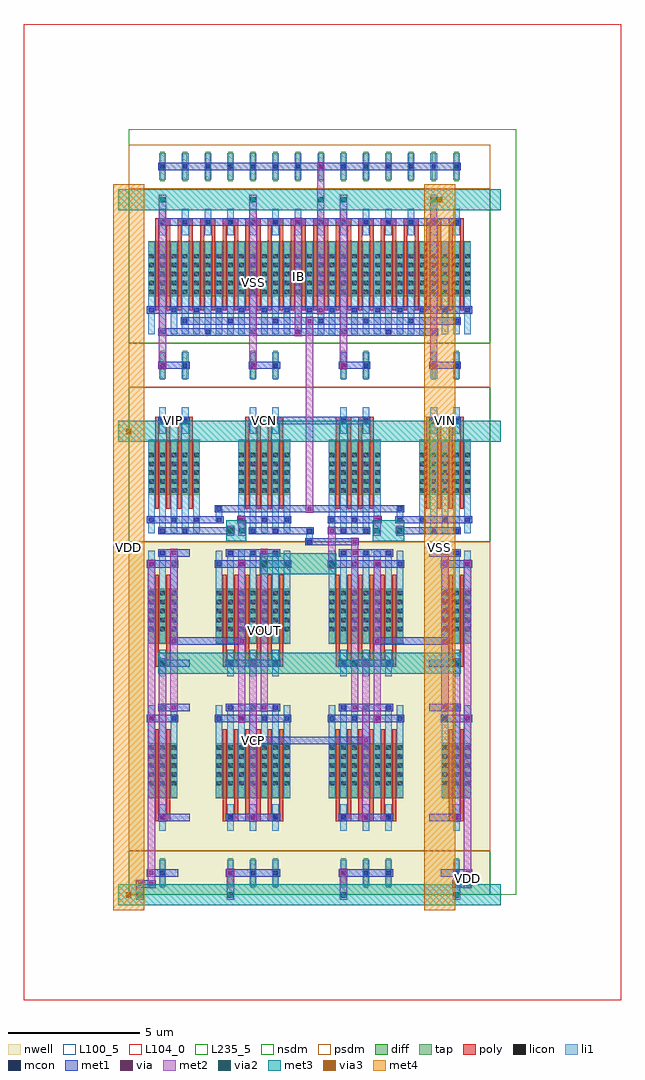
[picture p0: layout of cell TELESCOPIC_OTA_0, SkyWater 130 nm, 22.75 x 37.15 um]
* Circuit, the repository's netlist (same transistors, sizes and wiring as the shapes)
* NGSPICE file created from TELESCOPIC_OTA_0.ext - technology: sky130A

.subckt NMOS_4T_28886488_X2_Y1_1774869527 a_230_357# a_200_252# a_147_357# a_241_1232#
X0 a_230_357# a_200_252# a_147_357# a_241_1232# sky130_fd_pr__nfet_01v8 ad=0.294 pd=2.38 as=0.5565 ps=4.73 w=2.1 l=0.15 M=4
.ends

.subckt PMOS_S_89697479_X1_Y2_1774869529 a_230_357# a_200_252# w_0_0#
X0 a_230_357# a_200_252# w_0_0# w_0_0# sky130_fd_pr__pfet_01v8 ad=0.294 pd=2.38 as=0.5565 ps=4.73 w=2.1 l=0.15 M=4
.ends

.subckt PMOS_4T_8744924_X3_Y2_1774869528 a_230_357# a_200_252# a_147_357# w_0_0#
X0 a_230_357# a_200_252# a_147_357# w_0_0# sky130_fd_pr__pfet_01v8 ad=0.294 pd=2.38 as=0.5565 ps=4.73 w=2.1 l=0.15 M=12
.ends

.subckt SCM_NMOS_72619132_X7_Y1_1774869530 a_200_252# a_402_357# a_147_357#
X0 a_200_252# a_200_252# a_147_357# a_147_357# sky130_fd_pr__nfet_01v8 ad=0.294 pd=2.38 as=0.294 ps=2.38 w=2.1 l=0.15 M=14
X1 a_147_357# a_200_252# a_402_357# a_147_357# sky130_fd_pr__nfet_01v8 ad=0.294 pd=2.38 as=0.294 ps=2.38 w=2.1 l=0.15 M=14
.ends

.subckt TELESCOPIC_OTA_0 IB VCN VOUT VIP VIN VCP VSS VDD
XNMOS_4T_28886488_X2_Y1_1774869527_2 VOUT VCN m1_1860_2828# VSS NMOS_4T_28886488_X2_Y1_1774869527
XNMOS_4T_28886488_X2_Y1_1774869527_3 m2_230_1727# VCN m1_430_2744# VSS NMOS_4T_28886488_X2_Y1_1774869527
XPMOS_S_89697479_X1_Y2_1774869529_0 m1_312_1904# m2_230_1727# VDD PMOS_S_89697479_X1_Y2_1774869529
XPMOS_S_89697479_X1_Y2_1774869529_1 m1_1860_1904# m2_230_1727# VDD PMOS_S_89697479_X1_Y2_1774869529
XPMOS_4T_8744924_X3_Y2_1774869528_1 m2_230_1727# VCP m1_1860_1904# VDD PMOS_4T_8744924_X3_Y2_1774869528
XPMOS_4T_8744924_X3_Y2_1774869528_0 VOUT VCP m1_312_1904# VDD PMOS_4T_8744924_X3_Y2_1774869528
XSCM_NMOS_72619132_X7_Y1_1774869530_0 IB li_663_2839# VSS SCM_NMOS_72619132_X7_Y1_1774869530
XNMOS_4T_28886488_X2_Y1_1774869527_0 m1_1860_2828# VIN li_663_2839# VSS NMOS_4T_28886488_X2_Y1_1774869527
XNMOS_4T_28886488_X2_Y1_1774869527_1 m1_430_2744# VIP li_663_2839# VSS NMOS_4T_28886488_X2_Y1_1774869527
.ends

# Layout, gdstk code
from math import pi, radians
import gdstk
lib = gdstk.Library(unit=1e-6, precision=1e-09)
def R(c, l, rs):  # rectangles x0, y0, x1, y1
    for r in rs: c.add(gdstk.rectangle(r[:2], r[2:], *l))
def A(c, l, x, y, w, h, nx, ny, dx, dy):  # array of equal rectangles
    R(c, l, [(x+i*dx, y+j*dy, x+i*dx+w, y+j*dy+h) for i in range(nx) for j in range(ny)])
def P(c, l, *ps):  # polygons
    for p in ps: c.add(gdstk.Polygon(p, *l))
nwell = (64, 20)
diff = (65, 20)
tap = (65, 44)
poly = (66, 20)
licon = (66, 44)
li1 = (67, 20)
mcon = (67, 44)
met1 = (68, 20)
via = (68, 44)
met2 = (69, 20)
via2 = (69, 44)
met3 = (70, 20)
via3 = (70, 44)
met4 = (71, 20)
nsdm = (93, 44)
psdm = (94, 20)
L100_5 = (100, 5)
L104_0 = (104, 0)
L235_5 = (235, 5)

scm_nmos_72619132_x7_y1_ = lib.new_cell('SCM_NMOS_72619132_X7_Y1_1774869530')
R(scm_nmos_72619132_x7_y1_, diff, [(0.735,1.785,13.025,3.885)])
A(scm_nmos_72619132_x7_y1_, tap, 1.205, 6.16, 0.17, 1.12, 14, 1, 0.86, 0)
A(scm_nmos_72619132_x7_y1_, poly, 1, 1.26, 0.15, 3.36, 28, 1, 0.43, 0)
A(scm_nmos_72619132_x7_y1_, poly, 1, 4.485, 0.58, 0.27, 14, 1, 0.86, 0)
A(scm_nmos_72619132_x7_y1_, licon, 0.775, 1.865, 0.17, 0.17, 3, 5, 0.43, 0.34)
A(scm_nmos_72619132_x7_y1_, licon, 1.635, 1.865, 0.17, 0.17, 3, 5, 0.43, 0.34)
A(scm_nmos_72619132_x7_y1_, licon, 2.495, 1.865, 0.17, 0.17, 3, 5, 0.43, 0.34)
A(scm_nmos_72619132_x7_y1_, licon, 3.355, 1.865, 0.17, 0.17, 3, 5, 0.43, 0.34)
A(scm_nmos_72619132_x7_y1_, licon, 4.215, 1.865, 0.17, 0.17, 3, 5, 0.43, 0.34)
A(scm_nmos_72619132_x7_y1_, licon, 5.075, 1.865, 0.17, 0.17, 3, 5, 0.43, 0.34)
A(scm_nmos_72619132_x7_y1_, licon, 5.935, 1.865, 0.17, 0.17, 3, 5, 0.43, 0.34)
A(scm_nmos_72619132_x7_y1_, licon, 6.795, 1.865, 0.17, 0.17, 3, 5, 0.43, 0.34)
A(scm_nmos_72619132_x7_y1_, licon, 7.655, 1.865, 0.17, 0.17, 3, 5, 0.43, 0.34)
A(scm_nmos_72619132_x7_y1_, licon, 8.515, 1.865, 0.17, 0.17, 3, 5, 0.43, 0.34)
A(scm_nmos_72619132_x7_y1_, licon, 9.375, 1.865, 0.17, 0.17, 3, 5, 0.43, 0.34)
A(scm_nmos_72619132_x7_y1_, licon, 10.235, 1.865, 0.17, 0.17, 3, 5, 0.43, 0.34)
A(scm_nmos_72619132_x7_y1_, licon, 11.095, 1.865, 0.17, 0.17, 3, 5, 0.43, 0.34)
A(scm_nmos_72619132_x7_y1_, licon, 11.955, 1.865, 0.17, 0.17, 3, 5, 0.43, 0.34)
A(scm_nmos_72619132_x7_y1_, licon, 1.205, 4.535, 0.17, 0.17, 14, 2, 0.86, 2.1)
A(scm_nmos_72619132_x7_y1_, li1, 0.735, 0.335, 0.25, 3.53, 29, 1, 0.43, 0)
A(scm_nmos_72619132_x7_y1_, li1, 1.165, 4.115, 0.25, 1.01, 14, 2, 0.86, 2.1)
A(scm_nmos_72619132_x7_y1_, mcon, 1.205, 0.335, 0.17, 0.17, 7, 1, 1.72, 0)
A(scm_nmos_72619132_x7_y1_, mcon, 2.065, 0.755, 0.17, 0.17, 7, 1, 1.72, 0)
A(scm_nmos_72619132_x7_y1_, mcon, 0.775, 1.175, 0.17, 0.17, 15, 1, 0.86, 0)
A(scm_nmos_72619132_x7_y1_, mcon, 1.205, 4.535, 0.17, 0.17, 14, 2, 0.86, 2.1)
R(scm_nmos_72619132_x7_y1_, met1, [(1.12,0.28,11.78,0.56), (1.98,0.7,12.64,0.98), (0.69,1.12,13.07,1.4), (1.12,4.48,12.64,4.76), (1.12,6.58,12.64,6.86)])
R(scm_nmos_72619132_x7_y1_, via, [(6.375,0.345,6.525,0.495), (7.235,1.185,7.385,1.335), (6.375,4.545,6.525,4.695), (7.235,6.645,7.385,6.795)])
R(scm_nmos_72619132_x7_y1_, met2, [(6.31,0.26,6.59,4.78), (7.17,1.1,7.45,6.88)])
R(scm_nmos_72619132_x7_y1_, nsdm, [(0,0,13.76,5.88)])
R(scm_nmos_72619132_x7_y1_, psdm, [(0,5.88,13.76,7.56)])
R(scm_nmos_72619132_x7_y1_, L100_5, [(0,0,13.76,7.56)])

pmos_s_89697479_x1_y2_17 = lib.new_cell('PMOS_S_89697479_X1_Y2_1774869529')
R(pmos_s_89697479_x1_y2_17, nwell, [(0,0,2.58,13.44)])
R(pmos_s_89697479_x1_y2_17, diff, [(0.735,1.785,1.845,3.885), (0.735,7.665,1.845,9.765)])
R(pmos_s_89697479_x1_y2_17, tap, [(1.205,12.04,1.375,13.16)])
R(pmos_s_89697479_x1_y2_17, poly, [(1,1.26,1.15,4.62), (1.43,1.26,1.58,4.62), (1,4.485,1.58,4.755), (1,7.14,1.15,10.5), (1.43,7.14,1.58,10.5), (1,10.365,1.58,10.635)])
A(pmos_s_89697479_x1_y2_17, licon, 0.775, 1.865, 0.17, 0.17, 3, 5, 0.43, 0.34)
A(pmos_s_89697479_x1_y2_17, licon, 0.775, 7.745, 0.17, 0.17, 3, 5, 0.43, 0.34)
R(pmos_s_89697479_x1_y2_17, licon, [(1.205,4.535,1.375,4.705), (1.205,10.415,1.375,10.585), (1.205,12.515,1.375,12.685), (1.205,12.515,1.375,12.685)])
A(pmos_s_89697479_x1_y2_17, li1, 0.735, 0.335, 0.25, 3.53, 3, 2, 0.43, 5.88)
R(pmos_s_89697479_x1_y2_17, li1, [(1.165,4.115,1.415,5.125), (1.165,9.995,1.415,11.005), (1.165,12.095,1.415,13.105)])
R(pmos_s_89697479_x1_y2_17, mcon, [(1.205,0.335,1.375,0.505), (0.775,0.755,0.945,0.925), (1.635,0.755,1.805,0.925), (1.205,4.535,1.375,4.705), (1.205,6.215,1.375,6.385), (0.775,6.635,0.945,6.805), (1.635,6.635,1.805,6.805), (1.205,10.415,1.375,10.585), (1.205,12.515,1.375,12.685)])
A(pmos_s_89697479_x1_y2_17, met1, 0.69, 0.7, 1.2, 0.28, 1, 3, 0, 5.88)
R(pmos_s_89697479_x1_y2_17, met1, [(0.26,0.28,1.46,0.56), (0.26,4.48,1.46,4.76), (0.26,6.16,1.46,6.44), (0.26,10.36,1.46,10.64)])
A(pmos_s_89697479_x1_y2_17, via, 1.645, 0.765, 0.15, 0.15, 1, 3, 0, 5.88)
R(pmos_s_89697479_x1_y2_17, via, [(0.785,0.345,0.935,0.495), (1.215,4.545,1.365,4.695), (0.785,6.225,0.935,6.375), (1.215,10.425,1.365,10.575)])
R(pmos_s_89697479_x1_y2_17, met2, [(0.72,0.26,1,6.46), (1.58,0.68,1.86,12.76), (1.15,4.46,1.43,10.66)])
R(pmos_s_89697479_x1_y2_17, nsdm, [(0,11.76,2.58,13.44)])
R(pmos_s_89697479_x1_y2_17, psdm, [(0,0,2.58,11.76)])
R(pmos_s_89697479_x1_y2_17, L100_5, [(0,0,2.58,13.44)])

nmos_4t_28886488_x2_y1_1 = lib.new_cell('NMOS_4T_28886488_X2_Y1_1774869527')
R(nmos_4t_28886488_x2_y1_1, diff, [(0.735,1.785,2.705,3.885)])
R(nmos_4t_28886488_x2_y1_1, tap, [(1.205,6.16,1.375,7.28), (2.065,6.16,2.235,7.28)])
A(nmos_4t_28886488_x2_y1_1, poly, 1, 1.26, 0.15, 3.36, 4, 1, 0.43, 0)
R(nmos_4t_28886488_x2_y1_1, poly, [(1,4.485,1.58,4.755), (1.86,4.485,2.44,4.755)])
A(nmos_4t_28886488_x2_y1_1, licon, 0.775, 1.865, 0.17, 0.17, 3, 5, 0.43, 0.34)
A(nmos_4t_28886488_x2_y1_1, licon, 1.635, 1.865, 0.17, 0.17, 3, 5, 0.43, 0.34)
R(nmos_4t_28886488_x2_y1_1, licon, [(1.205,4.535,1.375,4.705), (2.065,4.535,2.235,4.705), (1.205,6.635,1.375,6.805), (2.065,6.635,2.235,6.805)])
A(nmos_4t_28886488_x2_y1_1, li1, 0.735, 0.335, 0.25, 3.53, 5, 1, 0.43, 0)
R(nmos_4t_28886488_x2_y1_1, li1, [(1.165,4.115,1.415,5.125), (2.025,4.115,2.275,5.125), (1.165,6.215,1.415,7.225), (2.025,6.215,2.275,7.225)])
A(nmos_4t_28886488_x2_y1_1, mcon, 0.775, 0.755, 0.17, 0.17, 3, 1, 0.86, 0)
R(nmos_4t_28886488_x2_y1_1, mcon, [(1.205,0.335,1.375,0.505), (2.065,0.335,2.235,0.505), (1.205,4.535,1.375,4.705), (2.065,4.535,2.235,4.705), (1.205,6.635,1.375,6.805), (2.065,6.635,2.235,6.805)])
R(nmos_4t_28886488_x2_y1_1, met1, [(1.12,0.28,2.32,0.56), (0.69,0.7,2.75,0.98), (1.12,4.48,2.32,4.76), (1.12,6.58,2.32,6.86)])
R(nmos_4t_28886488_x2_y1_1, nsdm, [(0,0,3.44,5.88)])
R(nmos_4t_28886488_x2_y1_1, psdm, [(0,5.88,3.44,7.56)])
R(nmos_4t_28886488_x2_y1_1, L100_5, [(0,0,3.44,7.56)])

pmos_4t_8744924_x3_y2_17 = lib.new_cell('PMOS_4T_8744924_X3_Y2_1774869528')
R(pmos_4t_8744924_x3_y2_17, nwell, [(0,0,4.3,13.44)])
R(pmos_4t_8744924_x3_y2_17, diff, [(0.735,1.785,3.565,3.885), (0.735,7.665,3.565,9.765)])
A(pmos_4t_8744924_x3_y2_17, tap, 1.205, 12.04, 0.17, 1.12, 3, 1, 0.86, 0)
A(pmos_4t_8744924_x3_y2_17, poly, 1, 1.26, 0.15, 3.36, 6, 2, 0.43, 5.88)
A(pmos_4t_8744924_x3_y2_17, poly, 1, 4.485, 0.58, 0.27, 3, 2, 0.86, 5.88)
A(pmos_4t_8744924_x3_y2_17, licon, 0.775, 1.865, 0.17, 0.17, 3, 5, 0.43, 0.34)
A(pmos_4t_8744924_x3_y2_17, licon, 1.635, 1.865, 0.17, 0.17, 3, 5, 0.43, 0.34)
A(pmos_4t_8744924_x3_y2_17, licon, 2.495, 1.865, 0.17, 0.17, 3, 5, 0.43, 0.34)
A(pmos_4t_8744924_x3_y2_17, licon, 1.205, 4.535, 0.17, 0.17, 3, 2, 0.86, 5.88)
A(pmos_4t_8744924_x3_y2_17, licon, 0.775, 7.745, 0.17, 0.17, 3, 5, 0.43, 0.34)
A(pmos_4t_8744924_x3_y2_17, licon, 1.635, 7.745, 0.17, 0.17, 3, 5, 0.43, 0.34)
A(pmos_4t_8744924_x3_y2_17, licon, 2.495, 7.745, 0.17, 0.17, 3, 5, 0.43, 0.34)
R(pmos_4t_8744924_x3_y2_17, licon, [(1.205,12.515,1.375,12.685), (1.205,12.515,1.375,12.685), (2.065,12.515,2.235,12.685), (2.065,12.515,2.235,12.685), (2.925,12.515,3.095,12.685), (2.925,12.515,3.095,12.685)])
A(pmos_4t_8744924_x3_y2_17, li1, 0.735, 0.335, 0.25, 3.53, 7, 2, 0.43, 5.88)
A(pmos_4t_8744924_x3_y2_17, li1, 1.165, 4.115, 0.25, 1.01, 3, 2, 0.86, 5.88)
A(pmos_4t_8744924_x3_y2_17, li1, 1.165, 12.095, 0.25, 1.01, 3, 1, 0.86, 0)
A(pmos_4t_8744924_x3_y2_17, mcon, 1.205, 0.335, 0.17, 0.17, 3, 2, 0.86, 4.2)
A(pmos_4t_8744924_x3_y2_17, mcon, 0.775, 0.755, 0.17, 0.17, 4, 2, 0.86, 5.88)
A(pmos_4t_8744924_x3_y2_17, mcon, 1.205, 6.215, 0.17, 0.17, 3, 2, 0.86, 4.2)
A(pmos_4t_8744924_x3_y2_17, mcon, 1.205, 12.515, 0.17, 0.17, 3, 1, 0.86, 0)
R(pmos_4t_8744924_x3_y2_17, met1, [(1.12,0.28,3.18,0.56), (0.69,0.7,3.61,0.98), (1.12,4.48,3.18,4.76), (1.12,6.16,3.18,6.44), (0.69,6.58,3.61,6.86), (1.12,10.36,3.18,10.64), (1.12,12.46,3.18,12.74)])
R(pmos_4t_8744924_x3_y2_17, via, [(1.645,0.345,1.795,0.495), (2.505,0.765,2.655,0.915), (2.075,4.545,2.225,4.695), (1.645,6.225,1.795,6.375), (2.505,6.645,2.655,6.795), (2.075,10.425,2.225,10.575)])
R(pmos_4t_8744924_x3_y2_17, met2, [(1.58,0.26,1.86,6.46), (2.44,0.68,2.72,6.88), (2.01,4.46,2.29,10.66)])
R(pmos_4t_8744924_x3_y2_17, nsdm, [(0,11.76,4.3,13.44)])
R(pmos_4t_8744924_x3_y2_17, psdm, [(0,0,4.3,11.76)])
R(pmos_4t_8744924_x3_y2_17, L100_5, [(0,0,4.3,13.44)])

telescopic_ota_0 = lib.new_cell('TELESCOPIC_OTA_0')
R(telescopic_ota_0, li1, [(6.755,13.355,7.005,13.525), (6.755,13.355,7.005,13.525), (6.755,13.44,7.005,13.86), (6.755,13.775,7.005,13.945), (6.755,13.775,7.005,13.945), (3.315,14.195,3.565,14.365), (3.315,14.195,3.565,14.365), (3.315,14.195,3.565,14.365), (3.315,14.195,3.565,14.365), (10.195,14.195,10.445,14.365), (10.195,14.195,10.445,14.365), (10.195,14.195,10.445,14.365), (10.195,14.195,10.445,14.365), (3.315,14.28,3.565,14.7), (10.195,14.28,10.445,14.7), (3.315,14.615,3.565,14.785), (3.315,14.615,3.565,14.785), (3.315,14.615,3.565,14.785), (3.315,14.615,3.565,14.785), (10.195,14.615,10.445,14.785), (10.195,14.615,10.445,14.785), (10.195,14.615,10.445,14.785), (10.195,14.615,10.445,14.785)])
R(telescopic_ota_0, mcon, [(6.795,13.355,6.965,13.525), (6.795,13.355,6.965,13.525), (6.795,13.775,6.965,13.945), (6.795,13.775,6.965,13.945), (3.355,14.195,3.525,14.365), (3.355,14.195,3.525,14.365), (3.355,14.195,3.525,14.365), (3.355,14.195,3.525,14.365), (10.235,14.195,10.405,14.365), (10.235,14.195,10.405,14.365), (10.235,14.195,10.405,14.365), (10.235,14.195,10.405,14.365), (3.355,14.615,3.525,14.785), (3.355,14.615,3.525,14.785), (3.355,14.615,3.525,14.785), (3.355,14.615,3.525,14.785), (10.235,14.615,10.405,14.785), (10.235,14.615,10.405,14.785), (10.235,14.615,10.405,14.785), (10.235,14.615,10.405,14.785)])
R(telescopic_ota_0, met1, [(0.27,0.28,0.59,0.56), (0.27,0.28,0.59,0.56), (0.27,0.28,0.59,0.56), (0.27,0.28,0.59,0.56), (0.43,0.28,0.86,0.56), (0.7,0.28,1.02,0.56), (0.7,0.28,1.02,0.56), (0.7,0.28,1.02,0.56), (0.7,0.28,1.02,0.56), (12.31,0.28,12.63,0.56), (12.31,0.28,12.63,0.56), (12.31,0.28,12.63,0.56), (12.31,0.28,12.63,0.56), (12.31,0.28,12.63,0.56), (12.47,0.28,12.9,0.56), (12.74,0.28,13.06,0.56), (12.74,0.28,13.06,0.56), (12.74,0.28,13.06,0.56), (12.74,0.28,13.06,0.56), (12.74,0.28,13.06,0.56), (3.71,0.7,4.03,0.98), (3.71,0.7,4.03,0.98), (8.01,0.7,8.33,0.98), (8.01,0.7,8.33,0.98), (8.01,0.7,8.33,0.98), (4.57,5.74,4.89,6.02), (4.57,5.74,4.89,6.02), (4.73,5.74,9.03,6.02), (8.87,5.74,9.19,6.02), (8.87,5.74,9.19,6.02), (1.56,9.52,1.88,9.8), (1.56,9.52,1.88,9.8), (1.72,9.52,4.3,9.8), (4.14,9.52,4.46,9.8), (4.14,9.52,4.46,9.8), (9.3,9.52,9.62,9.8), (9.3,9.52,9.62,9.8), (9.46,9.52,12.04,9.8), (11.88,9.52,12.2,9.8), (11.88,9.52,12.2,9.8), (6.71,13.3,7.05,13.58), (6.71,13.3,7.05,13.58), (6.88,13.3,8.6,13.58), (8.44,13.3,8.76,13.58), (8.44,13.3,8.76,13.58), (2.15,13.72,3.87,14), (3.71,13.72,4.03,14), (5.59,13.72,6.88,14), (6.71,13.72,7.05,14), (6.71,13.72,7.05,14), (7.58,13.72,7.9,14), (7.58,13.72,7.9,14), (7.74,13.72,8.17,14), (10.16,13.72,10.48,14), (10.32,13.72,11.61,14), (2.58,14.14,3.44,14.42), (3.27,14.14,3.61,14.42), (3.27,14.14,3.61,14.42), (3.27,14.14,3.61,14.42), (3.27,14.14,3.61,14.42), (4.14,14.14,4.46,14.42), (4.14,14.14,4.46,14.42), (9.3,14.14,9.62,14.42), (9.3,14.14,9.62,14.42), (10.15,14.14,10.49,14.42), (10.15,14.14,10.49,14.42), (10.15,14.14,10.49,14.42), (10.15,14.14,10.49,14.42), (10.32,14.14,11.18,14.42), (3.27,14.56,3.61,14.84), (3.27,14.56,3.61,14.84), (3.27,14.56,3.61,14.84), (3.27,14.56,3.61,14.84), (3.44,14.56,10.32,14.84), (6.72,14.56,7.04,14.84), (6.72,14.56,7.04,14.84), (10.15,14.56,10.49,14.84), (10.15,14.56,10.49,14.84), (10.15,14.56,10.49,14.84), (10.15,14.56,10.49,14.84), (5.59,17.92,8.17,18.2), (1.13,20.02,1.45,20.3), (1.13,20.02,1.45,20.3), (1.13,20.02,1.45,20.3), (4.57,20.02,4.89,20.3), (4.57,20.02,4.89,20.3), (4.57,20.02,4.89,20.3), (4.57,20.02,4.89,20.3), (4.57,20.02,4.89,20.3), (8.01,20.02,8.33,20.3), (8.01,20.02,8.33,20.3), (8.01,20.02,8.33,20.3), (8.01,20.02,8.33,20.3), (11.45,20.02,11.77,20.3), (11.45,20.02,11.77,20.3), (6.72,21.7,7.04,21.98), (6.72,21.7,7.04,21.98)])
P(telescopic_ota_0, met1, [(0,0),(0,0),(0,0),(0,0)],
  [(0,0),(0,0),(0,0),(0,0)],
  [(0,0),(0,0),(0,0),(0,0)],
  [(0,0),(0,0),(0,0),(0,0)],
  [(0,0),(0,0),(0,0),(0,0)],
  [(0,0),(0,0),(0,0),(0,0)],
  [(0,0),(0,0),(0,0),(0,0)],
  [(0,0),(0,0),(0,0),(0,0)],
  [(0,0),(0,0),(0,0),(0,0)],
  [(0,0),(0,0),(0,0),(0,0)],
  [(0,0),(0,0),(0,0),(0,0)],
  [(0,0),(0,0),(0,0),(0,0)],
  [(0,0),(0,0),(0,0),(0,0)],
  [(0,0),(0,0),(0,0),(0,0)],
  [(0,0),(0,0),(0,0),(0,0)],
  [(0,0),(0,0),(0,0),(0,0)],
  [(0,0),(0,0),(0,0),(0,0)],
  [(0,0),(0,0),(0,0),(0,0)],
  [(0,0),(0,0),(0,0),(0,0)],
  [(0,0),(0,0),(0,0),(0,0)],
  [(0,0),(0,0),(0,0),(0,0)],
  [(0,0),(0,0),(0,0),(0,0)])
R(telescopic_ota_0, via, [(0.355,0.345,0.505,0.495), (0.355,0.345,0.505,0.495), (0.355,0.345,0.505,0.495), (0.355,0.345,0.505,0.495), (0.785,0.345,0.935,0.495), (0.785,0.345,0.935,0.495), (0.785,0.345,0.935,0.495), (0.785,0.345,0.935,0.495), (12.395,0.345,12.545,0.495), (12.395,0.345,12.545,0.495), (12.395,0.345,12.545,0.495), (12.395,0.345,12.545,0.495), (12.395,0.345,12.545,0.495), (12.825,0.345,12.975,0.495), (12.825,0.345,12.975,0.495), (12.825,0.345,12.975,0.495), (12.825,0.345,12.975,0.495), (12.825,0.345,12.975,0.495), (3.795,0.765,3.945,0.915), (3.795,0.765,3.945,0.915), (8.095,0.765,8.245,0.915), (8.095,0.765,8.245,0.915), (8.095,0.765,8.245,0.915), (4.655,5.805,4.805,5.955), (4.655,5.805,4.805,5.955), (8.955,5.805,9.105,5.955), (8.955,5.805,9.105,5.955), (1.645,9.585,1.795,9.735), (1.645,9.585,1.795,9.735), (4.225,9.585,4.375,9.735), (4.225,9.585,4.375,9.735), (9.385,9.585,9.535,9.735), (9.385,9.585,9.535,9.735), (11.965,9.585,12.115,9.735), (11.965,9.585,12.115,9.735), (8.525,13.365,8.675,13.515), (8.525,13.365,8.675,13.515), (3.795,13.785,3.945,13.935), (7.665,13.785,7.815,13.935), (7.665,13.785,7.815,13.935), (10.245,13.785,10.395,13.935), (4.225,14.205,4.375,14.355), (4.225,14.205,4.375,14.355), (9.385,14.205,9.535,14.355), (9.385,14.205,9.535,14.355), (6.805,14.625,6.955,14.775), (6.805,14.625,6.955,14.775), (1.215,20.085,1.365,20.235), (1.215,20.085,1.365,20.235), (1.215,20.085,1.365,20.235), (4.655,20.085,4.805,20.235), (4.655,20.085,4.805,20.235), (4.655,20.085,4.805,20.235), (4.655,20.085,4.805,20.235), (4.655,20.085,4.805,20.235), (8.095,20.085,8.245,20.235), (8.095,20.085,8.245,20.235), (8.095,20.085,8.245,20.235), (8.095,20.085,8.245,20.235), (11.535,20.085,11.685,20.235), (11.535,20.085,11.685,20.235), (6.805,21.765,6.955,21.915), (6.805,21.765,6.955,21.915)])
A(telescopic_ota_0, met2, 1.15, 20.16, 0.28, 6.3, 4, 1, 3.44, 0)
R(telescopic_ota_0, met2, [(0.29,-0.185,0.57,0.185), (0.29,-0.185,0.57,0.185), (0.29,-0.185,0.57,0.185), (0.29,-0.185,0.57,0.185), (3.73,-0.185,4.01,0.185), (3.73,-0.185,4.01,0.185), (8.03,-0.185,8.31,0.185), (8.03,-0.185,8.31,0.185), (8.03,-0.185,8.31,0.185), (12.33,-0.185,12.61,0.185), (12.33,-0.185,12.61,0.185), (12.33,-0.185,12.61,0.185), (12.33,-0.185,12.61,0.185), (12.33,-0.185,12.61,0.185), (0.29,0,0.57,0.42), (3.73,0,4.01,0.84), (8.03,0,8.31,0.84), (12.33,0,12.61,0.42), (0.29,0.26,0.57,0.58), (0.29,0.26,0.57,0.58), (0.29,0.26,0.57,0.58), (0.29,0.26,0.57,0.58), (0.72,0.26,1,0.58), (0.72,0.26,1,0.58), (0.72,0.26,1,0.58), (0.72,0.26,1,0.58), (12.33,0.26,12.61,0.58), (12.33,0.26,12.61,0.58), (12.33,0.26,12.61,0.58), (12.33,0.26,12.61,0.58), (12.33,0.26,12.61,0.58), (12.76,0.26,13.04,0.58), (12.76,0.26,13.04,0.58), (12.76,0.26,13.04,0.58), (12.76,0.26,13.04,0.58), (12.76,0.26,13.04,0.58), (0.72,0.42,1,0.84), (12.76,0.42,13.04,0.84), (3.73,0.68,4.01,1), (3.73,0.68,4.01,1), (8.03,0.68,8.31,1), (8.03,0.68,8.31,1), (8.03,0.68,8.31,1), (4.59,5.72,4.87,6.04), (4.59,5.72,4.87,6.04), (8.89,5.72,9.17,6.04), (8.89,5.72,9.17,6.04), (1.15,8.635,1.43,9.005), (1.15,8.635,1.43,9.005), (1.15,8.635,1.43,9.005), (1.15,8.635,1.43,9.005), (1.15,8.635,1.43,9.005), (1.15,8.635,1.43,9.005), (8.46,8.635,8.74,9.005), (8.46,8.635,8.74,9.005), (8.46,8.635,8.74,9.005), (8.46,8.635,8.74,9.005), (12.33,8.635,12.61,9.005), (12.33,8.635,12.61,9.005), (12.33,8.635,12.61,9.005), (12.33,8.635,12.61,9.005), (12.33,8.635,12.61,9.005), (12.33,8.635,12.61,9.005), (1.58,9.5,1.86,9.82), (1.58,9.5,1.86,9.82), (4.16,9.5,4.44,9.82), (4.16,9.5,4.44,9.82), (9.32,9.5,9.6,9.82), (9.32,9.5,9.6,9.82), (11.9,9.5,12.18,9.82), (11.9,9.5,12.18,9.82), (5.02,12.415,5.3,12.785), (5.02,12.415,5.3,12.785), (7.6,12.415,7.88,12.785), (7.6,12.415,7.88,12.785), (7.6,12.6,7.88,13.86), (8.46,13.02,8.74,13.44), (8.46,13.28,8.74,13.6), (8.46,13.28,8.74,13.6), (3.73,13.675,4.01,14.045), (4.16,13.675,4.44,14.045), (4.16,13.675,4.44,14.045), (9.32,13.675,9.6,14.045), (9.32,13.675,9.6,14.045), (10.18,13.675,10.46,14.045), (3.73,13.7,4.01,14.02), (7.6,13.7,7.88,14.02), (7.6,13.7,7.88,14.02), (10.18,13.7,10.46,14.02), (3.73,13.739,4.01,13.981), (10.18,13.739,10.46,13.981), (4.16,13.86,4.44,14.28), (9.32,13.86,9.6,14.28), (4.16,14.12,4.44,14.44), (4.16,14.12,4.44,14.44), (9.32,14.12,9.6,14.44), (9.32,14.12,9.6,14.44), (6.74,14.54,7.02,14.86), (6.74,14.54,7.02,14.86), (6.74,14.7,7.02,21.84), (1.15,20,1.43,20.32), (1.15,20,1.43,20.32), (1.15,20,1.43,20.32), (4.59,20,4.87,20.32), (4.59,20,4.87,20.32), (4.59,20,4.87,20.32), (4.59,20,4.87,20.32), (4.59,20,4.87,20.32), (8.03,20,8.31,20.32), (8.03,20,8.31,20.32), (8.03,20,8.31,20.32), (8.03,20,8.31,20.32), (11.47,20,11.75,20.32), (11.47,20,11.75,20.32), (6.74,21.68,7.02,22), (6.74,21.68,7.02,22), (1.15,26.275,1.43,26.645), (1.15,26.275,1.43,26.645), (1.15,26.275,1.43,26.645), (4.59,26.275,4.87,26.645), (4.59,26.275,4.87,26.645), (4.59,26.275,4.87,26.645), (4.59,26.275,4.87,26.645), (4.59,26.275,4.87,26.645), (7.17,26.275,7.45,26.645), (7.17,26.275,7.45,26.645), (7.17,26.275,7.45,26.645), (7.17,26.275,7.45,26.645), (7.17,26.275,7.45,26.645), (7.17,26.275,7.45,26.645), (8.03,26.275,8.31,26.645), (8.03,26.275,8.31,26.645), (8.03,26.275,8.31,26.645), (8.03,26.275,8.31,26.645), (11.47,26.275,11.75,26.645), (11.47,26.275,11.75,26.645)])
P(telescopic_ota_0, met2, [(0,0),(0,0),(0,0),(0,0)],
  [(0,0),(0,0),(0,0),(0,0)],
  [(0,0),(0,0),(0,0),(0,0)],
  [(0,0),(0,0),(0,0),(0,0)],
  [(0,0),(0,0),(0,0),(0,0)],
  [(0,0),(0,0),(0,0),(0,0)],
  [(0,0),(0,0),(0,0),(0,0)],
  [(0,0),(0,0),(0,0),(0,0)],
  [(0,0),(0,0),(0,0),(0,0)],
  [(0,0),(0,0),(0,0),(0,0)],
  [(0,0),(0,0),(0,0),(0,0)],
  [(0,0),(0,0),(0,0),(0,0)],
  [(0,0),(0,0),(0,0),(0,0)],
  [(0,0),(0,0),(0,0),(0,0)],
  [(0,0),(0,0),(0,0),(0,0)],
  [(0,0),(0,0),(0,0),(0,0)],
  [(0,0),(0,0),(0,0),(0,0)])
R(telescopic_ota_0, via2, [(0.33,-0.1,0.53,0.1), (0.33,-0.1,0.53,0.1), (0.33,-0.1,0.53,0.1), (0.33,-0.1,0.53,0.1), (3.77,-0.1,3.97,0.1), (3.77,-0.1,3.97,0.1), (8.07,-0.1,8.27,0.1), (8.07,-0.1,8.27,0.1), (8.07,-0.1,8.27,0.1), (12.37,-0.1,12.57,0.1), (12.37,-0.1,12.57,0.1), (12.37,-0.1,12.57,0.1), (12.37,-0.1,12.57,0.1), (12.37,-0.1,12.57,0.1), (1.19,8.72,1.39,8.92), (1.19,8.72,1.39,8.92), (1.19,8.72,1.39,8.92), (1.19,8.72,1.39,8.92), (1.19,8.72,1.39,8.92), (1.19,8.72,1.39,8.92), (8.5,8.72,8.7,8.92), (8.5,8.72,8.7,8.92), (8.5,8.72,8.7,8.92), (8.5,8.72,8.7,8.92), (12.37,8.72,12.57,8.92), (12.37,8.72,12.57,8.92), (12.37,8.72,12.57,8.92), (12.37,8.72,12.57,8.92), (12.37,8.72,12.57,8.92), (12.37,8.72,12.57,8.92), (5.06,12.5,5.26,12.7), (5.06,12.5,5.26,12.7), (7.64,12.5,7.84,12.7), (7.64,12.5,7.84,12.7), (3.77,13.76,3.97,13.96), (4.2,13.76,4.4,13.96), (4.2,13.76,4.4,13.96), (9.36,13.76,9.56,13.96), (9.36,13.76,9.56,13.96), (10.22,13.76,10.42,13.96), (1.19,26.36,1.39,26.56), (1.19,26.36,1.39,26.56), (1.19,26.36,1.39,26.56), (4.63,26.36,4.83,26.56), (4.63,26.36,4.83,26.56), (4.63,26.36,4.83,26.56), (4.63,26.36,4.83,26.56), (4.63,26.36,4.83,26.56), (7.21,26.36,7.41,26.56), (7.21,26.36,7.41,26.56), (7.21,26.36,7.41,26.56), (7.21,26.36,7.41,26.56), (7.21,26.36,7.41,26.56), (7.21,26.36,7.41,26.56), (8.07,26.36,8.27,26.56), (8.07,26.36,8.27,26.56), (8.07,26.36,8.27,26.56), (8.07,26.36,8.27,26.56), (11.51,26.36,11.71,26.56), (11.51,26.36,11.71,26.56)])
A(telescopic_ota_0, met3, -0.4, -0.4, 4.24, 0.8, 3, 2, 3.44, 17.64)
A(telescopic_ota_0, met3, -0.4, 26.06, 4.24, 0.8, 3, 1, 3.44, 0)
R(telescopic_ota_0, met3, [(-0.165,-0.4,0.165,0.4), (0.265,-0.4,0.595,0.4), (0.265,-0.4,0.595,0.4), (0.265,-0.4,0.595,0.4), (0.265,-0.4,0.595,0.4), (3.705,-0.4,4.035,0.4), (3.705,-0.4,4.035,0.4), (8.005,-0.4,8.335,0.4), (8.005,-0.4,8.335,0.4), (8.005,-0.4,8.335,0.4), (9.92,-0.4,12.24,0.4), (11.44,-0.4,14.16,0.4), (12.305,-0.4,12.635,0.4), (12.305,-0.4,12.635,0.4), (12.305,-0.4,12.635,0.4), (12.305,-0.4,12.635,0.4), (12.305,-0.4,12.635,0.4), (1.125,8.42,1.455,9.22), (1.125,8.42,1.455,9.22), (1.125,8.42,1.455,9.22), (1.125,8.42,1.455,9.22), (1.125,8.42,1.455,9.22), (1.125,8.42,1.455,9.22), (1.29,8.42,12.47,9.22), (8.435,8.42,8.765,9.22), (8.435,8.42,8.765,9.22), (8.435,8.42,8.765,9.22), (8.435,8.42,8.765,9.22), (12.305,8.42,12.635,9.22), (12.305,8.42,12.635,9.22), (12.305,8.42,12.635,9.22), (12.305,8.42,12.635,9.22), (12.305,8.42,12.635,9.22), (12.305,8.42,12.635,9.22), (4.995,12.2,5.325,13), (4.995,12.2,5.325,13), (5.16,12.2,7.74,13), (7.575,12.2,7.905,13), (7.575,12.2,7.905,13), (3.705,13.46,4.035,14.26), (3.87,13.46,4.3,14.26), (4.135,13.46,4.465,14.26), (4.135,13.46,4.465,14.26), (9.295,13.46,9.625,14.26), (9.295,13.46,9.625,14.26), (9.46,13.46,10.32,14.26), (10.155,13.46,10.485,14.26), (-0.165,17.24,0.165,18.04), (9.92,17.24,12.24,18.04), (11.44,17.24,14.16,18.04), (1.125,26.06,1.455,26.86), (1.125,26.06,1.455,26.86), (1.125,26.06,1.455,26.86), (4.565,26.06,4.895,26.86), (4.565,26.06,4.895,26.86), (4.565,26.06,4.895,26.86), (4.565,26.06,4.895,26.86), (4.565,26.06,4.895,26.86), (7.145,26.06,7.475,26.86), (7.145,26.06,7.475,26.86), (7.145,26.06,7.475,26.86), (7.145,26.06,7.475,26.86), (7.145,26.06,7.475,26.86), (7.145,26.06,7.475,26.86), (8.005,26.06,8.335,26.86), (8.005,26.06,8.335,26.86), (8.005,26.06,8.335,26.86), (8.005,26.06,8.335,26.86), (9.92,26.06,12.24,26.86), (11.44,26.06,14.16,26.86), (11.445,26.06,11.775,26.86), (11.445,26.06,11.775,26.86), (11.675,26.06,12.005,26.86)])
R(telescopic_ota_0, via3, [(-0.1,-0.1,0.1,0.1), (-0.1,17.54,0.1,17.74), (11.74,26.36,11.94,26.56)])
A(telescopic_ota_0, met4, -0.59, -0.59, 1.18, 10, 1, 3, 0, 8.82)
A(telescopic_ota_0, met4, 11.25, -0.59, 1.18, 10, 1, 3, 0, 8.82)
R(telescopic_ota_0, met4, [(-0.59,-0.165,0.59,0.165), (-0.59,17.475,0.59,17.805), (11.25,26.295,12.43,26.625)])
R(telescopic_ota_0, L104_0, [(-4,-4,18.75,33.15)])
R(telescopic_ota_0, L235_5, [(0,0,14.75,29.15)])
telescopic_ota_0.add(gdstk.Reference(scm_nmos_72619132_x7_y1_, (0,21)))
telescopic_ota_0.add(gdstk.Reference(pmos_s_89697479_x1_y2_17, (11.18,13.44), x_reflection=True))
telescopic_ota_0.add(gdstk.Reference(pmos_s_89697479_x1_y2_17, (2.58,13.44), rotation=pi))
telescopic_ota_0.add(gdstk.Reference(nmos_4t_28886488_x2_y1_1, (3.44,13.44)))
telescopic_ota_0.add(gdstk.Reference(nmos_4t_28886488_x2_y1_1, (10.32,13.44), rotation=pi, x_reflection=True))
telescopic_ota_0.add(gdstk.Reference(nmos_4t_28886488_x2_y1_1, (3.44,13.44), rotation=pi, x_reflection=True))
telescopic_ota_0.add(gdstk.Reference(nmos_4t_28886488_x2_y1_1, (10.32,13.44)))
telescopic_ota_0.add(gdstk.Reference(pmos_4t_8744924_x3_y2_17, (6.88,13.44), x_reflection=True))
telescopic_ota_0.add(gdstk.Reference(pmos_4t_8744924_x3_y2_17, (6.88,13.44), rotation=pi))
telescopic_ota_0.add(gdstk.Label('IB', (6.45,23.52), layer=69, texttype=5))
telescopic_ota_0.add(gdstk.Label('VCN', (5.16,18.06), layer=68, texttype=5))
telescopic_ota_0.add(gdstk.Label('VOUT', (5.16,10.08), layer=69, texttype=5))
telescopic_ota_0.add(gdstk.Label('VIP', (1.72,18.06), layer=68, texttype=5))
telescopic_ota_0.add(gdstk.Label('VIN', (12.04,18.06), layer=68, texttype=5))
telescopic_ota_0.add(gdstk.Label('VCP', (4.73,5.88), layer=69, texttype=5))
telescopic_ota_0.add(gdstk.Label('VSS', (11.84,13.23), layer=71, texttype=5))
telescopic_ota_0.add(gdstk.Label('VSS', (11.84,13.23), layer=71, texttype=5))
telescopic_ota_0.add(gdstk.Label('VSS', (11.84,13.23), layer=71, texttype=5))
telescopic_ota_0.add(gdstk.Label('VSS', (4.73,23.31), layer=69, texttype=5))
telescopic_ota_0.add(gdstk.Label('VSS', (11.84,13.23), layer=71, texttype=5))
telescopic_ota_0.add(gdstk.Label('VSS', (11.84,13.23), layer=71, texttype=5))
telescopic_ota_0.add(gdstk.Label('VSS', (11.84,13.23), layer=71, texttype=5))
telescopic_ota_0.add(gdstk.Label('VSS', (11.84,13.23), layer=71, texttype=5))
telescopic_ota_0.add(gdstk.Label('VSS', (11.84,13.23), layer=71, texttype=5))
telescopic_ota_0.add(gdstk.Label('VSS', (11.84,13.23), layer=71, texttype=5))
telescopic_ota_0.add(gdstk.Label('VSS', (11.84,13.23), layer=71, texttype=5))
telescopic_ota_0.add(gdstk.Label('VSS', (11.84,13.23), layer=71, texttype=5))
telescopic_ota_0.add(gdstk.Label('VSS', (11.84,13.23), layer=71, texttype=5))
telescopic_ota_0.add(gdstk.Label('VSS', (11.84,13.23), layer=71, texttype=5))
telescopic_ota_0.add(gdstk.Label('VSS', (11.84,13.23), layer=71, texttype=5))
telescopic_ota_0.add(gdstk.Label('VDD', (12.9,0.63), layer=69, texttype=5))
telescopic_ota_0.add(gdstk.Label('VDD', (0,13.23), layer=71, texttype=5))
telescopic_ota_0.add(gdstk.Label('VDD', (0,13.23), layer=71, texttype=5))
telescopic_ota_0.add(gdstk.Label('VDD', (0,13.23), layer=71, texttype=5))
telescopic_ota_0.add(gdstk.Label('VDD', (0,13.23), layer=71, texttype=5))
telescopic_ota_0.add(gdstk.Label('VDD', (0,13.23), layer=71, texttype=5))
telescopic_ota_0.add(gdstk.Label('VDD', (0,13.23), layer=71, texttype=5))
telescopic_ota_0.add(gdstk.Label('VDD', (0,13.23), layer=71, texttype=5))
telescopic_ota_0.add(gdstk.Label('VDD', (0,13.23), layer=71, texttype=5))
telescopic_ota_0.add(gdstk.Label('VDD', (0,13.23), layer=71, texttype=5))
telescopic_ota_0.add(gdstk.Label('VDD', (0,13.23), layer=71, texttype=5))
telescopic_ota_0.add(gdstk.Label('VDD', (0,13.23), layer=71, texttype=5))
telescopic_ota_0.add(gdstk.Label('VDD', (0,13.23), layer=71, texttype=5))
telescopic_ota_0.add(gdstk.Label('VDD', (0,13.23), layer=71, texttype=5))
telescopic_ota_0.add(gdstk.Label('VDD', (0,13.23), layer=71, texttype=5))

lib.write_gds('TELESCOPIC_OTA_0.gds')
